VERSION 5.7 ;
  NOWIREEXTENSIONATPIN ON ;
  DIVIDERCHAR "/" ;
  BUSBITCHARS "[]" ;
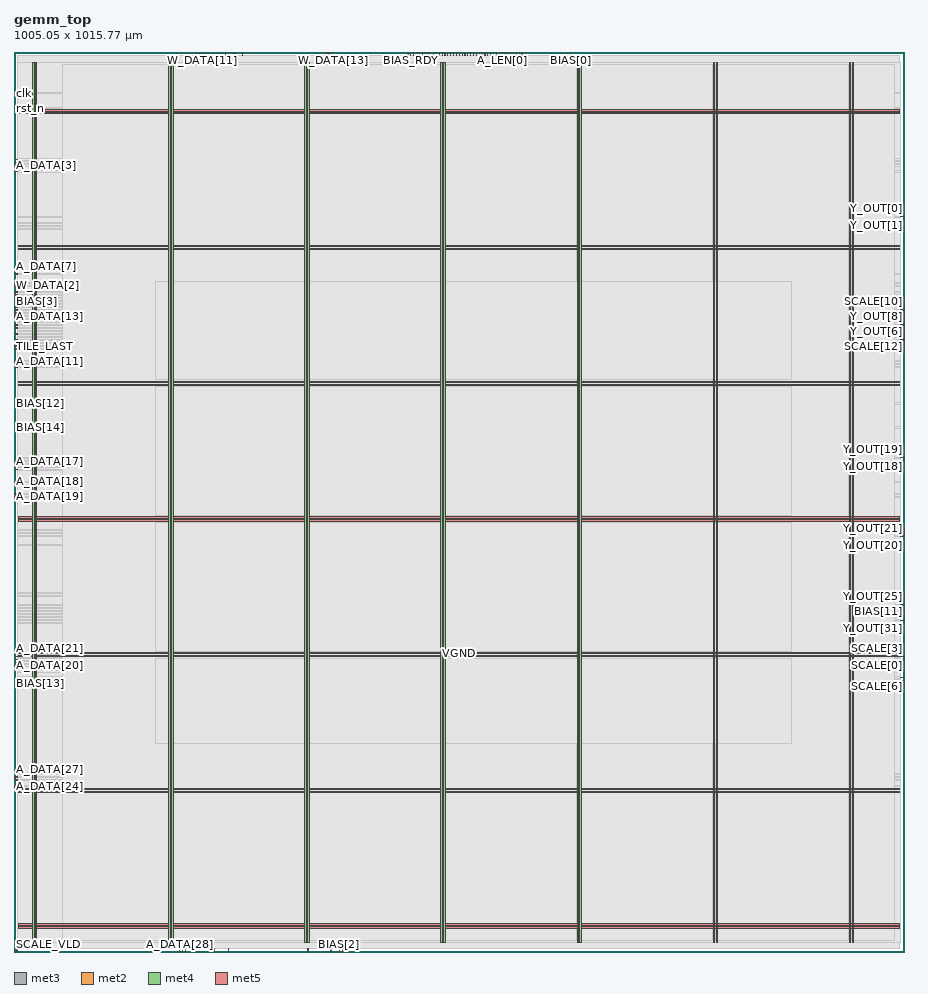
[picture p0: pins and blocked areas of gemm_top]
MACRO gemm_top
  CLASS BLOCK ;
  FOREIGN gemm_top ;
  ORIGIN 0.000 0.000 ;
  SIZE 1005.050 BY 1015.770 ;
  PIN A_DATA[0]
    DIRECTION INPUT ;
    USE SIGNAL ;
    ANTENNAGATEAREA 0.213000 ;
    PORT
      LAYER met3 ;
        RECT 0.000 894.240 4.000 894.840 ;
    END
  END A_DATA[0]
  PIN A_DATA[10]
    DIRECTION INPUT ;
    USE SIGNAL ;
    ANTENNAGATEAREA 0.213000 ;
    PORT
      LAYER met3 ;
        RECT 0.000 697.040 4.000 697.640 ;
    END
  END A_DATA[10]
  PIN A_DATA[11]
    DIRECTION INPUT ;
    USE SIGNAL ;
    ANTENNAGATEAREA 0.213000 ;
    PORT
      LAYER met3 ;
        RECT 0.000 666.440 4.000 667.040 ;
    END
  END A_DATA[11]
  PIN A_DATA[12]
    DIRECTION INPUT ;
    USE SIGNAL ;
    ANTENNAGATEAREA 0.159000 ;
    PORT
      LAYER met3 ;
        RECT 0.000 707.240 4.000 707.840 ;
    END
  END A_DATA[12]
  PIN A_DATA[13]
    DIRECTION INPUT ;
    USE SIGNAL ;
    ANTENNAGATEAREA 0.159000 ;
    PORT
      LAYER met3 ;
        RECT 0.000 717.440 4.000 718.040 ;
    END
  END A_DATA[13]
  PIN A_DATA[14]
    DIRECTION INPUT ;
    USE SIGNAL ;
    ANTENNAGATEAREA 0.159000 ;
    PORT
      LAYER met3 ;
        RECT 0.000 720.840 4.000 721.440 ;
    END
  END A_DATA[14]
  PIN A_DATA[15]
    DIRECTION INPUT ;
    USE SIGNAL ;
    ANTENNAGATEAREA 0.159000 ;
    PORT
      LAYER met3 ;
        RECT 0.000 703.840 4.000 704.440 ;
    END
  END A_DATA[15]
  PIN A_DATA[16]
    DIRECTION INPUT ;
    USE SIGNAL ;
    ANTENNAGATEAREA 0.213000 ;
    PORT
      LAYER met3 ;
        RECT 0.000 516.840 4.000 517.440 ;
    END
  END A_DATA[16]
  PIN A_DATA[17]
    DIRECTION INPUT ;
    USE SIGNAL ;
    ANTENNAGATEAREA 0.213000 ;
    PORT
      LAYER met3 ;
        RECT 0.000 544.040 4.000 544.640 ;
    END
  END A_DATA[17]
  PIN A_DATA[18]
    DIRECTION INPUT ;
    USE SIGNAL ;
    ANTENNAGATEAREA 0.213000 ;
    PORT
      LAYER met3 ;
        RECT 0.000 530.440 4.000 531.040 ;
    END
  END A_DATA[18]
  PIN A_DATA[19]
    DIRECTION INPUT ;
    USE SIGNAL ;
    ANTENNAGATEAREA 0.213000 ;
    PORT
      LAYER met3 ;
        RECT 0.000 513.440 4.000 514.040 ;
    END
  END A_DATA[19]
  PIN A_DATA[1]
    DIRECTION INPUT ;
    USE SIGNAL ;
    ANTENNAGATEAREA 0.213000 ;
    PORT
      LAYER met3 ;
        RECT 0.000 880.640 4.000 881.240 ;
    END
  END A_DATA[1]
  PIN A_DATA[20]
    DIRECTION INPUT ;
    USE SIGNAL ;
    ANTENNAGATEAREA 0.159000 ;
    PORT
      LAYER met3 ;
        RECT 0.000 323.040 4.000 323.640 ;
    END
  END A_DATA[20]
  PIN A_DATA[21]
    DIRECTION INPUT ;
    USE SIGNAL ;
    ANTENNAGATEAREA 0.159000 ;
    PORT
      LAYER met3 ;
        RECT 0.000 333.240 4.000 333.840 ;
    END
  END A_DATA[21]
  PIN A_DATA[22]
    DIRECTION INPUT ;
    USE SIGNAL ;
    ANTENNAGATEAREA 0.159000 ;
    PORT
      LAYER met3 ;
        RECT 0.000 326.440 4.000 327.040 ;
    END
  END A_DATA[22]
  PIN A_DATA[23]
    DIRECTION INPUT ;
    USE SIGNAL ;
    ANTENNAGATEAREA 0.213000 ;
    PORT
      LAYER met3 ;
        RECT 0.000 329.840 4.000 330.440 ;
    END
  END A_DATA[23]
  PIN A_DATA[24]
    DIRECTION INPUT ;
    USE SIGNAL ;
    ANTENNAGATEAREA 0.159000 ;
    PORT
      LAYER met3 ;
        RECT 0.000 187.040 4.000 187.640 ;
    END
  END A_DATA[24]
  PIN A_DATA[25]
    DIRECTION INPUT ;
    USE SIGNAL ;
    ANTENNAGATEAREA 0.159000 ;
    PORT
      LAYER met3 ;
        RECT 0.000 193.840 4.000 194.440 ;
    END
  END A_DATA[25]
  PIN A_DATA[26]
    DIRECTION INPUT ;
    USE SIGNAL ;
    ANTENNAGATEAREA 0.159000 ;
    PORT
      LAYER met3 ;
        RECT 0.000 200.640 4.000 201.240 ;
    END
  END A_DATA[26]
  PIN A_DATA[27]
    DIRECTION INPUT ;
    USE SIGNAL ;
    ANTENNAGATEAREA 0.159000 ;
    PORT
      LAYER met3 ;
        RECT 0.000 197.240 4.000 197.840 ;
    END
  END A_DATA[27]
  PIN A_DATA[28]
    DIRECTION INPUT ;
    USE SIGNAL ;
    ANTENNAGATEAREA 0.213000 ;
    PORT
      LAYER met2 ;
        RECT 186.850 0.000 187.130 4.000 ;
    END
  END A_DATA[28]
  PIN A_DATA[29]
    DIRECTION INPUT ;
    USE SIGNAL ;
    ANTENNAGATEAREA 0.159000 ;
    PORT
      LAYER met2 ;
        RECT 190.070 0.000 190.350 4.000 ;
    END
  END A_DATA[29]
  PIN A_DATA[2]
    DIRECTION INPUT ;
    USE SIGNAL ;
    ANTENNAGATEAREA 0.159000 ;
    PORT
      LAYER met3 ;
        RECT 0.000 890.840 4.000 891.440 ;
    END
  END A_DATA[2]
  PIN A_DATA[30]
    DIRECTION INPUT ;
    USE SIGNAL ;
    ANTENNAGATEAREA 0.213000 ;
    PORT
      LAYER met2 ;
        RECT 193.290 0.000 193.570 4.000 ;
    END
  END A_DATA[30]
  PIN A_DATA[31]
    DIRECTION INPUT ;
    USE SIGNAL ;
    ANTENNAGATEAREA 0.159000 ;
    PORT
      LAYER met2 ;
        RECT 202.950 0.000 203.230 4.000 ;
    END
  END A_DATA[31]
  PIN A_DATA[3]
    DIRECTION INPUT ;
    USE SIGNAL ;
    ANTENNAGATEAREA 0.213000 ;
    PORT
      LAYER met3 ;
        RECT 0.000 887.440 4.000 888.040 ;
    END
  END A_DATA[3]
  PIN A_DATA[4]
    DIRECTION INPUT ;
    USE SIGNAL ;
    ANTENNAGATEAREA 0.213000 ;
    PORT
      LAYER met3 ;
        RECT 0.000 741.240 4.000 741.840 ;
    END
  END A_DATA[4]
  PIN A_DATA[5]
    DIRECTION INPUT ;
    USE SIGNAL ;
    ANTENNAGATEAREA 0.213000 ;
    PORT
      LAYER met3 ;
        RECT 0.000 727.640 4.000 728.240 ;
    END
  END A_DATA[5]
  PIN A_DATA[6]
    DIRECTION INPUT ;
    USE SIGNAL ;
    ANTENNAGATEAREA 0.213000 ;
    PORT
      LAYER met3 ;
        RECT 0.000 724.240 4.000 724.840 ;
    END
  END A_DATA[6]
  PIN A_DATA[7]
    DIRECTION INPUT ;
    USE SIGNAL ;
    ANTENNAGATEAREA 0.213000 ;
    PORT
      LAYER met3 ;
        RECT 0.000 765.040 4.000 765.640 ;
    END
  END A_DATA[7]
  PIN A_DATA[8]
    DIRECTION INPUT ;
    USE SIGNAL ;
    ANTENNAGATEAREA 0.213000 ;
    PORT
      LAYER met3 ;
        RECT 0.000 663.040 4.000 663.640 ;
    END
  END A_DATA[8]
  PIN A_DATA[9]
    DIRECTION INPUT ;
    USE SIGNAL ;
    ANTENNAGATEAREA 0.213000 ;
    PORT
      LAYER met3 ;
        RECT 0.000 680.040 4.000 680.640 ;
    END
  END A_DATA[9]
  PIN A_LEN[0]
    DIRECTION INPUT ;
    USE SIGNAL ;
    ANTENNAGATEAREA 0.213000 ;
    PORT
      LAYER met2 ;
        RECT 550.710 1011.770 550.990 1015.770 ;
    END
  END A_LEN[0]
  PIN A_LEN[1]
    DIRECTION INPUT ;
    USE SIGNAL ;
    ANTENNAGATEAREA 0.159000 ;
    PORT
      LAYER met2 ;
        RECT 547.490 1011.770 547.770 1015.770 ;
    END
  END A_LEN[1]
  PIN A_LEN[2]
    DIRECTION INPUT ;
    USE SIGNAL ;
    ANTENNAGATEAREA 0.213000 ;
    PORT
      LAYER met2 ;
        RECT 531.390 1011.770 531.670 1015.770 ;
    END
  END A_LEN[2]
  PIN A_LEN[3]
    DIRECTION INPUT ;
    USE SIGNAL ;
    ANTENNAGATEAREA 0.213000 ;
    PORT
      LAYER met2 ;
        RECT 515.290 1011.770 515.570 1015.770 ;
    END
  END A_LEN[3]
  PIN BIAS[0]
    DIRECTION INPUT ;
    USE SIGNAL ;
    ANTENNAGATEAREA 0.742500 ;
    PORT
      LAYER met2 ;
        RECT 627.990 1011.770 628.270 1015.770 ;
    END
  END BIAS[0]
  PIN BIAS[10]
    DIRECTION INPUT ;
    USE SIGNAL ;
    ANTENNAGATEAREA 0.742500 ;
    PORT
      LAYER met2 ;
        RECT 225.490 0.000 225.770 4.000 ;
    END
  END BIAS[10]
  PIN BIAS[11]
    DIRECTION INPUT ;
    USE SIGNAL ;
    ANTENNAGATEAREA 0.495000 ;
    PORT
      LAYER met3 ;
        RECT 1001.050 384.240 1005.050 384.840 ;
    END
  END BIAS[11]
  PIN BIAS[12]
    DIRECTION INPUT ;
    USE SIGNAL ;
    ANTENNAGATEAREA 0.990000 ;
    PORT
      LAYER met3 ;
        RECT 0.000 618.840 4.000 619.440 ;
    END
  END BIAS[12]
  PIN BIAS[13]
    DIRECTION INPUT ;
    USE SIGNAL ;
    ANTENNAGATEAREA 0.852000 ;
    PORT
      LAYER met3 ;
        RECT 0.000 302.640 4.000 303.240 ;
    END
  END BIAS[13]
  PIN BIAS[14]
    DIRECTION INPUT ;
    USE SIGNAL ;
    ANTENNAGATEAREA 0.247500 ;
    PORT
      LAYER met3 ;
        RECT 0.000 591.640 4.000 592.240 ;
    END
  END BIAS[14]
  PIN BIAS[15]
    DIRECTION INPUT ;
    USE SIGNAL ;
    ANTENNAGATEAREA 0.426000 ;
    PORT
      LAYER met3 ;
        RECT 0.000 690.240 4.000 690.840 ;
    END
  END BIAS[15]
  PIN BIAS[1]
    DIRECTION INPUT ;
    USE SIGNAL ;
    ANTENNAGATEAREA 0.742500 ;
    PORT
      LAYER met2 ;
        RECT 444.450 1011.770 444.730 1015.770 ;
    END
  END BIAS[1]
  PIN BIAS[2]
    DIRECTION INPUT ;
    USE SIGNAL ;
    ANTENNAGATEAREA 0.742500 ;
    PORT
      LAYER met2 ;
        RECT 367.170 0.000 367.450 4.000 ;
    END
  END BIAS[2]
  PIN BIAS[3]
    DIRECTION INPUT ;
    USE SIGNAL ;
    ANTENNAGATEAREA 0.742500 ;
    PORT
      LAYER met3 ;
        RECT 0.000 734.440 4.000 735.040 ;
    END
  END BIAS[3]
  PIN BIAS[4]
    DIRECTION INPUT ;
    USE SIGNAL ;
    ANTENNAGATEAREA 0.852000 ;
    PORT
      LAYER met2 ;
        RECT 241.590 0.000 241.870 4.000 ;
    END
  END BIAS[4]
  PIN BIAS[5]
    DIRECTION INPUT ;
    USE SIGNAL ;
    ANTENNAGATEAREA 0.990000 ;
    PORT
      LAYER met2 ;
        RECT 370.390 0.000 370.670 4.000 ;
    END
  END BIAS[5]
  PIN BIAS[6]
    DIRECTION INPUT ;
    USE SIGNAL ;
    ANTENNAGATEAREA 0.742500 ;
    PORT
      LAYER met2 ;
        RECT 331.750 0.000 332.030 4.000 ;
    END
  END BIAS[6]
  PIN BIAS[7]
    DIRECTION INPUT ;
    USE SIGNAL ;
    ANTENNAGATEAREA 0.495000 ;
    PORT
      LAYER met2 ;
        RECT 357.510 0.000 357.790 4.000 ;
    END
  END BIAS[7]
  PIN BIAS[8]
    DIRECTION INPUT ;
    USE SIGNAL ;
    ANTENNAGATEAREA 0.990000 ;
    PORT
      LAYER met2 ;
        RECT 373.610 0.000 373.890 4.000 ;
    END
  END BIAS[8]
  PIN BIAS[9]
    DIRECTION INPUT ;
    USE SIGNAL ;
    ANTENNAGATEAREA 0.495000 ;
    PORT
      LAYER met3 ;
        RECT 0.000 659.640 4.000 660.240 ;
    END
  END BIAS[9]
  PIN BIAS_NEW
    DIRECTION INPUT ;
    USE SIGNAL ;
    ANTENNAGATEAREA 0.196500 ;
    PORT
      LAYER met2 ;
        RECT 537.830 1011.770 538.110 1015.770 ;
    END
  END BIAS_NEW
  PIN BIAS_RDY
    DIRECTION OUTPUT ;
    USE SIGNAL ;
    ANTENNADIFFAREA 0.445500 ;
    PORT
      LAYER met2 ;
        RECT 447.670 1011.770 447.950 1015.770 ;
    END
  END BIAS_RDY
  PIN BIAS_VLD
    DIRECTION INPUT ;
    USE SIGNAL ;
    ANTENNAGATEAREA 0.196500 ;
    PORT
      LAYER met2 ;
        RECT 454.110 1011.770 454.390 1015.770 ;
    END
  END BIAS_VLD
  PIN DATA_RDY
    DIRECTION OUTPUT ;
    USE SIGNAL ;
    ANTENNADIFFAREA 0.445500 ;
    PORT
      LAYER met2 ;
        RECT 483.090 1011.770 483.370 1015.770 ;
    END
  END DATA_RDY
  PIN DATA_VLD
    DIRECTION INPUT ;
    USE SIGNAL ;
    ANTENNAGATEAREA 0.196500 ;
    PORT
      LAYER met2 ;
        RECT 470.210 1011.770 470.490 1015.770 ;
    END
  END DATA_VLD
  PIN K_LEN[0]
    DIRECTION INPUT ;
    USE SIGNAL ;
    ANTENNAGATEAREA 0.196500 ;
    PORT
      LAYER met2 ;
        RECT 466.990 1011.770 467.270 1015.770 ;
    END
  END K_LEN[0]
  PIN K_LEN[1]
    DIRECTION INPUT ;
    USE SIGNAL ;
    ANTENNAGATEAREA 0.196500 ;
    PORT
      LAYER met2 ;
        RECT 463.770 1011.770 464.050 1015.770 ;
    END
  END K_LEN[1]
  PIN K_LEN[2]
    DIRECTION INPUT ;
    USE SIGNAL ;
    ANTENNAGATEAREA 0.196500 ;
    PORT
      LAYER met2 ;
        RECT 499.190 1011.770 499.470 1015.770 ;
    END
  END K_LEN[2]
  PIN K_LEN[3]
    DIRECTION INPUT ;
    USE SIGNAL ;
    ANTENNAGATEAREA 0.126000 ;
    PORT
      LAYER met2 ;
        RECT 521.730 1011.770 522.010 1015.770 ;
    END
  END K_LEN[3]
  PIN METADATA_RDY
    DIRECTION OUTPUT ;
    USE SIGNAL ;
    ANTENNADIFFAREA 0.445500 ;
    PORT
      LAYER met2 ;
        RECT 450.890 1011.770 451.170 1015.770 ;
    END
  END METADATA_RDY
  PIN METADATA_VLD
    DIRECTION INPUT ;
    USE SIGNAL ;
    ANTENNAGATEAREA 0.196500 ;
    PORT
      LAYER met2 ;
        RECT 457.330 1011.770 457.610 1015.770 ;
    END
  END METADATA_VLD
  PIN RELU_EN
    DIRECTION INPUT ;
    USE SIGNAL ;
    ANTENNAGATEAREA 0.196500 ;
    PORT
      LAYER met2 ;
        RECT 528.170 1011.770 528.450 1015.770 ;
    END
  END RELU_EN
  PIN SCALE[0]
    DIRECTION INPUT ;
    USE SIGNAL ;
    ANTENNAGATEAREA 0.159000 ;
    PORT
      LAYER met3 ;
        RECT 1001.050 323.040 1005.050 323.640 ;
    END
  END SCALE[0]
  PIN SCALE[10]
    DIRECTION INPUT ;
    USE SIGNAL ;
    ANTENNAGATEAREA 0.213000 ;
    PORT
      LAYER met3 ;
        RECT 1001.050 734.440 1005.050 735.040 ;
    END
  END SCALE[10]
  PIN SCALE[11]
    DIRECTION INPUT ;
    USE SIGNAL ;
    ANTENNAGATEAREA 0.196500 ;
    PORT
      LAYER met3 ;
        RECT 1001.050 727.640 1005.050 728.240 ;
    END
  END SCALE[11]
  PIN SCALE[12]
    DIRECTION INPUT ;
    USE SIGNAL ;
    ANTENNAGATEAREA 0.126000 ;
    PORT
      LAYER met3 ;
        RECT 1001.050 683.440 1005.050 684.040 ;
    END
  END SCALE[12]
  PIN SCALE[13]
    DIRECTION INPUT ;
    USE SIGNAL ;
    ANTENNAGATEAREA 0.159000 ;
    PORT
      LAYER met3 ;
        RECT 1001.050 720.840 1005.050 721.440 ;
    END
  END SCALE[13]
  PIN SCALE[14]
    DIRECTION INPUT ;
    USE SIGNAL ;
    ANTENNAGATEAREA 0.426000 ;
    PORT
      LAYER met3 ;
        RECT 1001.050 731.040 1005.050 731.640 ;
    END
  END SCALE[14]
  PIN SCALE[15]
    DIRECTION INPUT ;
    USE SIGNAL ;
    PORT
      LAYER met2 ;
        RECT 0.090 0.000 0.370 4.000 ;
    END
  END SCALE[15]
  PIN SCALE[1]
    DIRECTION INPUT ;
    USE SIGNAL ;
    ANTENNAGATEAREA 0.196500 ;
    PORT
      LAYER met3 ;
        RECT 1001.050 326.440 1005.050 327.040 ;
    END
  END SCALE[1]
  PIN SCALE[2]
    DIRECTION INPUT ;
    USE SIGNAL ;
    ANTENNAGATEAREA 0.196500 ;
    PORT
      LAYER met3 ;
        RECT 1001.050 329.840 1005.050 330.440 ;
    END
  END SCALE[2]
  PIN SCALE[3]
    DIRECTION INPUT ;
    USE SIGNAL ;
    ANTENNAGATEAREA 0.196500 ;
    PORT
      LAYER met3 ;
        RECT 1001.050 333.240 1005.050 333.840 ;
    END
  END SCALE[3]
  PIN SCALE[4]
    DIRECTION INPUT ;
    USE SIGNAL ;
    ANTENNAGATEAREA 0.196500 ;
    PORT
      LAYER met3 ;
        RECT 1001.050 336.640 1005.050 337.240 ;
    END
  END SCALE[4]
  PIN SCALE[5]
    DIRECTION INPUT ;
    USE SIGNAL ;
    ANTENNAGATEAREA 0.213000 ;
    PORT
      LAYER met3 ;
        RECT 1001.050 316.240 1005.050 316.840 ;
    END
  END SCALE[5]
  PIN SCALE[6]
    DIRECTION INPUT ;
    USE SIGNAL ;
    ANTENNAGATEAREA 0.247500 ;
    PORT
      LAYER met3 ;
        RECT 1001.050 299.240 1005.050 299.840 ;
    END
  END SCALE[6]
  PIN SCALE[7]
    DIRECTION INPUT ;
    USE SIGNAL ;
    ANTENNAGATEAREA 0.196500 ;
    PORT
      LAYER met3 ;
        RECT 1001.050 302.640 1005.050 303.240 ;
    END
  END SCALE[7]
  PIN SCALE[8]
    DIRECTION INPUT ;
    USE SIGNAL ;
    ANTENNAGATEAREA 0.247500 ;
    PORT
      LAYER met3 ;
        RECT 1001.050 306.040 1005.050 306.640 ;
    END
  END SCALE[8]
  PIN SCALE[9]
    DIRECTION INPUT ;
    USE SIGNAL ;
    ANTENNAGATEAREA 0.159000 ;
    PORT
      LAYER met3 ;
        RECT 1001.050 309.440 1005.050 310.040 ;
    END
  END SCALE[9]
  PIN SCALE_RDY
    DIRECTION OUTPUT ;
    USE SIGNAL ;
    ANTENNADIFFAREA 0.445500 ;
    PORT
      LAYER met2 ;
        RECT 508.850 1011.770 509.130 1015.770 ;
    END
  END SCALE_RDY
  PIN SCALE_VLD
    DIRECTION INPUT ;
    USE SIGNAL ;
    PORT
      LAYER met2 ;
        RECT 3.310 0.000 3.590 4.000 ;
    END
  END SCALE_VLD
  PIN TILE_DONE
    DIRECTION OUTPUT ;
    USE SIGNAL ;
    ANTENNADIFFAREA 0.445500 ;
    PORT
      LAYER met2 ;
        RECT 492.750 1011.770 493.030 1015.770 ;
    END
  END TILE_DONE
  PIN TILE_LAST
    DIRECTION INPUT ;
    USE SIGNAL ;
    ANTENNAGATEAREA 0.247500 ;
    PORT
      LAYER met3 ;
        RECT 0.000 683.440 4.000 684.040 ;
    END
  END TILE_LAST
  PIN TILE_START
    DIRECTION INPUT ;
    USE SIGNAL ;
    ANTENNAGATEAREA 0.196500 ;
    PORT
      LAYER met2 ;
        RECT 473.430 1011.770 473.710 1015.770 ;
    END
  END TILE_START
  PIN VGND
    DIRECTION INOUT ;
    USE GROUND ;
    PORT
      LAYER met4 ;
        RECT 24.340 10.640 25.940 1003.920 ;
    END
    PORT
      LAYER met4 ;
        RECT 177.940 10.640 179.540 1003.920 ;
    END
    PORT
      LAYER met4 ;
        RECT 331.540 10.640 333.140 1003.920 ;
    END
    PORT
      LAYER met4 ;
        RECT 485.140 10.640 486.740 1003.920 ;
    END
    PORT
      LAYER met4 ;
        RECT 638.740 10.640 640.340 1003.920 ;
    END
    PORT
      LAYER met4 ;
        RECT 792.340 10.640 793.940 1003.920 ;
    END
    PORT
      LAYER met4 ;
        RECT 945.940 10.640 947.540 1003.920 ;
    END
    PORT
      LAYER met5 ;
        RECT 5.280 30.030 999.360 31.630 ;
    END
    PORT
      LAYER met5 ;
        RECT 5.280 183.210 999.360 184.810 ;
    END
    PORT
      LAYER met5 ;
        RECT 5.280 336.390 999.360 337.990 ;
    END
    PORT
      LAYER met5 ;
        RECT 5.280 489.570 999.360 491.170 ;
    END
    PORT
      LAYER met5 ;
        RECT 5.280 642.750 999.360 644.350 ;
    END
    PORT
      LAYER met5 ;
        RECT 5.280 795.930 999.360 797.530 ;
    END
    PORT
      LAYER met5 ;
        RECT 5.280 949.110 999.360 950.710 ;
    END
  END VGND
  PIN VPWR
    DIRECTION INOUT ;
    USE POWER ;
    PORT
      LAYER met4 ;
        RECT 21.040 10.640 22.640 1003.920 ;
    END
    PORT
      LAYER met4 ;
        RECT 174.640 10.640 176.240 1003.920 ;
    END
    PORT
      LAYER met4 ;
        RECT 328.240 10.640 329.840 1003.920 ;
    END
    PORT
      LAYER met4 ;
        RECT 481.840 10.640 483.440 1003.920 ;
    END
    PORT
      LAYER met4 ;
        RECT 635.440 10.640 637.040 1003.920 ;
    END
    PORT
      LAYER met4 ;
        RECT 789.040 10.640 790.640 1003.920 ;
    END
    PORT
      LAYER met4 ;
        RECT 942.640 10.640 944.240 1003.920 ;
    END
    PORT
      LAYER met5 ;
        RECT 5.280 26.730 999.360 28.330 ;
    END
    PORT
      LAYER met5 ;
        RECT 5.280 179.910 999.360 181.510 ;
    END
    PORT
      LAYER met5 ;
        RECT 5.280 333.090 999.360 334.690 ;
    END
    PORT
      LAYER met5 ;
        RECT 5.280 486.270 999.360 487.870 ;
    END
    PORT
      LAYER met5 ;
        RECT 5.280 639.450 999.360 641.050 ;
    END
    PORT
      LAYER met5 ;
        RECT 5.280 792.630 999.360 794.230 ;
    END
    PORT
      LAYER met5 ;
        RECT 5.280 945.810 999.360 947.410 ;
    END
  END VPWR
  PIN W_DATA[0]
    DIRECTION INPUT ;
    USE SIGNAL ;
    ANTENNAGATEAREA 0.213000 ;
    PORT
      LAYER met3 ;
        RECT 0.000 737.840 4.000 738.440 ;
    END
  END W_DATA[0]
  PIN W_DATA[10]
    DIRECTION INPUT ;
    USE SIGNAL ;
    ANTENNAGATEAREA 0.213000 ;
    PORT
      LAYER met2 ;
        RECT 183.630 1011.770 183.910 1015.770 ;
    END
  END W_DATA[10]
  PIN W_DATA[11]
    DIRECTION INPUT ;
    USE SIGNAL ;
    ANTENNAGATEAREA 0.213000 ;
    PORT
      LAYER met2 ;
        RECT 212.610 1011.770 212.890 1015.770 ;
    END
  END W_DATA[11]
  PIN W_DATA[12]
    DIRECTION INPUT ;
    USE SIGNAL ;
    ANTENNAGATEAREA 0.213000 ;
    PORT
      LAYER met2 ;
        RECT 351.070 1011.770 351.350 1015.770 ;
    END
  END W_DATA[12]
  PIN W_DATA[13]
    DIRECTION INPUT ;
    USE SIGNAL ;
    ANTENNAGATEAREA 0.213000 ;
    PORT
      LAYER met2 ;
        RECT 360.730 1011.770 361.010 1015.770 ;
    END
  END W_DATA[13]
  PIN W_DATA[14]
    DIRECTION INPUT ;
    USE SIGNAL ;
    ANTENNAGATEAREA 0.213000 ;
    PORT
      LAYER met2 ;
        RECT 354.290 1011.770 354.570 1015.770 ;
    END
  END W_DATA[14]
  PIN W_DATA[15]
    DIRECTION INPUT ;
    USE SIGNAL ;
    ANTENNAGATEAREA 0.213000 ;
    PORT
      LAYER met2 ;
        RECT 357.510 1011.770 357.790 1015.770 ;
    END
  END W_DATA[15]
  PIN W_DATA[16]
    DIRECTION INPUT ;
    USE SIGNAL ;
    ANTENNAGATEAREA 0.213000 ;
    PORT
      LAYER met2 ;
        RECT 460.550 1011.770 460.830 1015.770 ;
    END
  END W_DATA[16]
  PIN W_DATA[17]
    DIRECTION INPUT ;
    USE SIGNAL ;
    ANTENNAGATEAREA 0.213000 ;
    PORT
      LAYER met2 ;
        RECT 502.410 1011.770 502.690 1015.770 ;
    END
  END W_DATA[17]
  PIN W_DATA[18]
    DIRECTION INPUT ;
    USE SIGNAL ;
    ANTENNAGATEAREA 0.213000 ;
    PORT
      LAYER met2 ;
        RECT 486.310 1011.770 486.590 1015.770 ;
    END
  END W_DATA[18]
  PIN W_DATA[19]
    DIRECTION INPUT ;
    USE SIGNAL ;
    ANTENNAGATEAREA 0.213000 ;
    PORT
      LAYER met2 ;
        RECT 495.970 1011.770 496.250 1015.770 ;
    END
  END W_DATA[19]
  PIN W_DATA[1]
    DIRECTION INPUT ;
    USE SIGNAL ;
    ANTENNAGATEAREA 0.213000 ;
    PORT
      LAYER met3 ;
        RECT 0.000 754.840 4.000 755.440 ;
    END
  END W_DATA[1]
  PIN W_DATA[20]
    DIRECTION INPUT ;
    USE SIGNAL ;
    ANTENNAGATEAREA 0.159000 ;
    PORT
      LAYER met2 ;
        RECT 489.530 1011.770 489.810 1015.770 ;
    END
  END W_DATA[20]
  PIN W_DATA[21]
    DIRECTION INPUT ;
    USE SIGNAL ;
    ANTENNAGATEAREA 0.159000 ;
    PORT
      LAYER met2 ;
        RECT 476.650 1011.770 476.930 1015.770 ;
    END
  END W_DATA[21]
  PIN W_DATA[22]
    DIRECTION INPUT ;
    USE SIGNAL ;
    ANTENNAGATEAREA 0.213000 ;
    PORT
      LAYER met2 ;
        RECT 524.950 1011.770 525.230 1015.770 ;
    END
  END W_DATA[22]
  PIN W_DATA[23]
    DIRECTION INPUT ;
    USE SIGNAL ;
    ANTENNAGATEAREA 0.159000 ;
    PORT
      LAYER met2 ;
        RECT 479.870 1011.770 480.150 1015.770 ;
    END
  END W_DATA[23]
  PIN W_DATA[24]
    DIRECTION INPUT ;
    USE SIGNAL ;
    ANTENNAGATEAREA 0.159000 ;
    PORT
      LAYER met2 ;
        RECT 563.590 1011.770 563.870 1015.770 ;
    END
  END W_DATA[24]
  PIN W_DATA[25]
    DIRECTION INPUT ;
    USE SIGNAL ;
    ANTENNAGATEAREA 0.213000 ;
    PORT
      LAYER met2 ;
        RECT 553.930 1011.770 554.210 1015.770 ;
    END
  END W_DATA[25]
  PIN W_DATA[26]
    DIRECTION INPUT ;
    USE SIGNAL ;
    ANTENNAGATEAREA 0.159000 ;
    PORT
      LAYER met2 ;
        RECT 541.050 1011.770 541.330 1015.770 ;
    END
  END W_DATA[26]
  PIN W_DATA[27]
    DIRECTION INPUT ;
    USE SIGNAL ;
    ANTENNAGATEAREA 0.213000 ;
    PORT
      LAYER met2 ;
        RECT 560.370 1011.770 560.650 1015.770 ;
    END
  END W_DATA[27]
  PIN W_DATA[28]
    DIRECTION INPUT ;
    USE SIGNAL ;
    ANTENNAGATEAREA 0.159000 ;
    PORT
      LAYER met2 ;
        RECT 557.150 1011.770 557.430 1015.770 ;
    END
  END W_DATA[28]
  PIN W_DATA[29]
    DIRECTION INPUT ;
    USE SIGNAL ;
    ANTENNAGATEAREA 0.159000 ;
    PORT
      LAYER met2 ;
        RECT 573.250 1011.770 573.530 1015.770 ;
    END
  END W_DATA[29]
  PIN W_DATA[2]
    DIRECTION INPUT ;
    USE SIGNAL ;
    ANTENNAGATEAREA 0.213000 ;
    PORT
      LAYER met3 ;
        RECT 0.000 751.440 4.000 752.040 ;
    END
  END W_DATA[2]
  PIN W_DATA[30]
    DIRECTION INPUT ;
    USE SIGNAL ;
    ANTENNAGATEAREA 0.159000 ;
    PORT
      LAYER met2 ;
        RECT 570.030 1011.770 570.310 1015.770 ;
    END
  END W_DATA[30]
  PIN W_DATA[31]
    DIRECTION INPUT ;
    USE SIGNAL ;
    ANTENNAGATEAREA 0.159000 ;
    PORT
      LAYER met2 ;
        RECT 566.810 1011.770 567.090 1015.770 ;
    END
  END W_DATA[31]
  PIN W_DATA[3]
    DIRECTION INPUT ;
    USE SIGNAL ;
    ANTENNAGATEAREA 0.213000 ;
    PORT
      LAYER met3 ;
        RECT 0.000 744.640 4.000 745.240 ;
    END
  END W_DATA[3]
  PIN W_DATA[4]
    DIRECTION INPUT ;
    USE SIGNAL ;
    ANTENNAGATEAREA 0.213000 ;
    PORT
      LAYER met2 ;
        RECT 257.690 1011.770 257.970 1015.770 ;
    END
  END W_DATA[4]
  PIN W_DATA[5]
    DIRECTION INPUT ;
    USE SIGNAL ;
    ANTENNAGATEAREA 0.213000 ;
    PORT
      LAYER met2 ;
        RECT 238.370 1011.770 238.650 1015.770 ;
    END
  END W_DATA[5]
  PIN W_DATA[6]
    DIRECTION INPUT ;
    USE SIGNAL ;
    ANTENNAGATEAREA 0.213000 ;
    PORT
      LAYER met2 ;
        RECT 235.150 1011.770 235.430 1015.770 ;
    END
  END W_DATA[6]
  PIN W_DATA[7]
    DIRECTION INPUT ;
    USE SIGNAL ;
    ANTENNAGATEAREA 0.159000 ;
    PORT
      LAYER met2 ;
        RECT 248.030 1011.770 248.310 1015.770 ;
    END
  END W_DATA[7]
  PIN W_DATA[8]
    DIRECTION INPUT ;
    USE SIGNAL ;
    ANTENNAGATEAREA 0.213000 ;
    PORT
      LAYER met2 ;
        RECT 209.390 1011.770 209.670 1015.770 ;
    END
  END W_DATA[8]
  PIN W_DATA[9]
    DIRECTION INPUT ;
    USE SIGNAL ;
    ANTENNAGATEAREA 0.213000 ;
    PORT
      LAYER met2 ;
        RECT 206.170 1011.770 206.450 1015.770 ;
    END
  END W_DATA[9]
  PIN W_LEN[0]
    DIRECTION INPUT ;
    USE SIGNAL ;
    ANTENNAGATEAREA 0.213000 ;
    PORT
      LAYER met2 ;
        RECT 512.070 1011.770 512.350 1015.770 ;
    END
  END W_LEN[0]
  PIN W_LEN[1]
    DIRECTION INPUT ;
    USE SIGNAL ;
    ANTENNAGATEAREA 0.159000 ;
    PORT
      LAYER met2 ;
        RECT 534.610 1011.770 534.890 1015.770 ;
    END
  END W_LEN[1]
  PIN W_LEN[2]
    DIRECTION INPUT ;
    USE SIGNAL ;
    ANTENNAGATEAREA 0.213000 ;
    PORT
      LAYER met2 ;
        RECT 518.510 1011.770 518.790 1015.770 ;
    END
  END W_LEN[2]
  PIN W_LEN[3]
    DIRECTION INPUT ;
    USE SIGNAL ;
    ANTENNAGATEAREA 0.213000 ;
    PORT
      LAYER met2 ;
        RECT 544.270 1011.770 544.550 1015.770 ;
    END
  END W_LEN[3]
  PIN Y_OUT[0]
    DIRECTION OUTPUT ;
    USE SIGNAL ;
    ANTENNADIFFAREA 0.445500 ;
    PORT
      LAYER met3 ;
        RECT 1001.050 829.640 1005.050 830.240 ;
    END
  END Y_OUT[0]
  PIN Y_OUT[10]
    DIRECTION OUTPUT ;
    USE SIGNAL ;
    ANTENNADIFFAREA 0.445500 ;
    PORT
      LAYER met3 ;
        RECT 1001.050 707.240 1005.050 707.840 ;
    END
  END Y_OUT[10]
  PIN Y_OUT[11]
    DIRECTION OUTPUT ;
    USE SIGNAL ;
    ANTENNADIFFAREA 0.445500 ;
    PORT
      LAYER met3 ;
        RECT 1001.050 686.840 1005.050 687.440 ;
    END
  END Y_OUT[11]
  PIN Y_OUT[12]
    DIRECTION OUTPUT ;
    USE SIGNAL ;
    ANTENNADIFFAREA 0.445500 ;
    PORT
      LAYER met3 ;
        RECT 1001.050 703.840 1005.050 704.440 ;
    END
  END Y_OUT[12]
  PIN Y_OUT[13]
    DIRECTION OUTPUT ;
    USE SIGNAL ;
    ANTENNADIFFAREA 0.445500 ;
    PORT
      LAYER met3 ;
        RECT 1001.050 710.640 1005.050 711.240 ;
    END
  END Y_OUT[13]
  PIN Y_OUT[14]
    DIRECTION OUTPUT ;
    USE SIGNAL ;
    ANTENNADIFFAREA 0.445500 ;
    PORT
      LAYER met3 ;
        RECT 1001.050 690.240 1005.050 690.840 ;
    END
  END Y_OUT[14]
  PIN Y_OUT[15]
    DIRECTION OUTPUT ;
    USE SIGNAL ;
    ANTENNADIFFAREA 0.445500 ;
    PORT
      LAYER met3 ;
        RECT 1001.050 680.040 1005.050 680.640 ;
    END
  END Y_OUT[15]
  PIN Y_OUT[16]
    DIRECTION OUTPUT ;
    USE SIGNAL ;
    ANTENNADIFFAREA 0.445500 ;
    PORT
      LAYER met3 ;
        RECT 1001.050 550.840 1005.050 551.440 ;
    END
  END Y_OUT[16]
  PIN Y_OUT[17]
    DIRECTION OUTPUT ;
    USE SIGNAL ;
    ANTENNADIFFAREA 0.445500 ;
    PORT
      LAYER met3 ;
        RECT 1001.050 554.240 1005.050 554.840 ;
    END
  END Y_OUT[17]
  PIN Y_OUT[18]
    DIRECTION OUTPUT ;
    USE SIGNAL ;
    ANTENNADIFFAREA 0.445500 ;
    PORT
      LAYER met3 ;
        RECT 1001.050 547.440 1005.050 548.040 ;
    END
  END Y_OUT[18]
  PIN Y_OUT[19]
    DIRECTION OUTPUT ;
    USE SIGNAL ;
    ANTENNADIFFAREA 0.445500 ;
    PORT
      LAYER met3 ;
        RECT 1001.050 557.640 1005.050 558.240 ;
    END
  END Y_OUT[19]
  PIN Y_OUT[1]
    DIRECTION OUTPUT ;
    USE SIGNAL ;
    ANTENNADIFFAREA 0.445500 ;
    PORT
      LAYER met3 ;
        RECT 1001.050 819.440 1005.050 820.040 ;
    END
  END Y_OUT[1]
  PIN Y_OUT[20]
    DIRECTION OUTPUT ;
    USE SIGNAL ;
    ANTENNADIFFAREA 0.445500 ;
    PORT
      LAYER met3 ;
        RECT 1001.050 459.040 1005.050 459.640 ;
    END
  END Y_OUT[20]
  PIN Y_OUT[21]
    DIRECTION OUTPUT ;
    USE SIGNAL ;
    ANTENNADIFFAREA 0.445500 ;
    PORT
      LAYER met3 ;
        RECT 1001.050 469.240 1005.050 469.840 ;
    END
  END Y_OUT[21]
  PIN Y_OUT[22]
    DIRECTION OUTPUT ;
    USE SIGNAL ;
    ANTENNADIFFAREA 0.445500 ;
    PORT
      LAYER met3 ;
        RECT 1001.050 472.640 1005.050 473.240 ;
    END
  END Y_OUT[22]
  PIN Y_OUT[23]
    DIRECTION OUTPUT ;
    USE SIGNAL ;
    ANTENNADIFFAREA 0.445500 ;
    PORT
      LAYER met3 ;
        RECT 1001.050 476.040 1005.050 476.640 ;
    END
  END Y_OUT[23]
  PIN Y_OUT[24]
    DIRECTION OUTPUT ;
    USE SIGNAL ;
    ANTENNADIFFAREA 0.445500 ;
    PORT
      LAYER met3 ;
        RECT 1001.050 391.040 1005.050 391.640 ;
    END
  END Y_OUT[24]
  PIN Y_OUT[25]
    DIRECTION OUTPUT ;
    USE SIGNAL ;
    ANTENNADIFFAREA 0.445500 ;
    PORT
      LAYER met3 ;
        RECT 1001.050 401.240 1005.050 401.840 ;
    END
  END Y_OUT[25]
  PIN Y_OUT[26]
    DIRECTION OUTPUT ;
    USE SIGNAL ;
    ANTENNADIFFAREA 0.445500 ;
    PORT
      LAYER met3 ;
        RECT 1001.050 387.640 1005.050 388.240 ;
    END
  END Y_OUT[26]
  PIN Y_OUT[27]
    DIRECTION OUTPUT ;
    USE SIGNAL ;
    ANTENNADIFFAREA 0.445500 ;
    PORT
      LAYER met3 ;
        RECT 1001.050 404.640 1005.050 405.240 ;
    END
  END Y_OUT[27]
  PIN Y_OUT[28]
    DIRECTION OUTPUT ;
    USE SIGNAL ;
    ANTENNADIFFAREA 0.445500 ;
    PORT
      LAYER met3 ;
        RECT 1001.050 377.440 1005.050 378.040 ;
    END
  END Y_OUT[28]
  PIN Y_OUT[29]
    DIRECTION OUTPUT ;
    USE SIGNAL ;
    ANTENNADIFFAREA 0.445500 ;
    PORT
      LAYER met3 ;
        RECT 1001.050 380.840 1005.050 381.440 ;
    END
  END Y_OUT[29]
  PIN Y_OUT[2]
    DIRECTION OUTPUT ;
    USE SIGNAL ;
    ANTENNADIFFAREA 0.445500 ;
    PORT
      LAYER met3 ;
        RECT 1001.050 816.040 1005.050 816.640 ;
    END
  END Y_OUT[2]
  PIN Y_OUT[30]
    DIRECTION OUTPUT ;
    USE SIGNAL ;
    ANTENNADIFFAREA 0.445500 ;
    PORT
      LAYER met3 ;
        RECT 1001.050 370.640 1005.050 371.240 ;
    END
  END Y_OUT[30]
  PIN Y_OUT[31]
    DIRECTION OUTPUT ;
    USE SIGNAL ;
    ANTENNADIFFAREA 0.445500 ;
    PORT
      LAYER met3 ;
        RECT 1001.050 374.040 1005.050 374.640 ;
    END
  END Y_OUT[31]
  PIN Y_OUT[3]
    DIRECTION OUTPUT ;
    USE SIGNAL ;
    ANTENNADIFFAREA 0.445500 ;
    PORT
      LAYER met3 ;
        RECT 1001.050 822.840 1005.050 823.440 ;
    END
  END Y_OUT[3]
  PIN Y_OUT[4]
    DIRECTION OUTPUT ;
    USE SIGNAL ;
    ANTENNADIFFAREA 0.445500 ;
    PORT
      LAYER met3 ;
        RECT 1001.050 714.040 1005.050 714.640 ;
    END
  END Y_OUT[4]
  PIN Y_OUT[5]
    DIRECTION OUTPUT ;
    USE SIGNAL ;
    ANTENNADIFFAREA 0.445500 ;
    PORT
      LAYER met3 ;
        RECT 1001.050 697.040 1005.050 697.640 ;
    END
  END Y_OUT[5]
  PIN Y_OUT[6]
    DIRECTION OUTPUT ;
    USE SIGNAL ;
    ANTENNADIFFAREA 0.445500 ;
    PORT
      LAYER met3 ;
        RECT 1001.050 700.440 1005.050 701.040 ;
    END
  END Y_OUT[6]
  PIN Y_OUT[7]
    DIRECTION OUTPUT ;
    USE SIGNAL ;
    ANTENNADIFFAREA 0.445500 ;
    PORT
      LAYER met3 ;
        RECT 1001.050 693.640 1005.050 694.240 ;
    END
  END Y_OUT[7]
  PIN Y_OUT[8]
    DIRECTION OUTPUT ;
    USE SIGNAL ;
    ANTENNADIFFAREA 0.445500 ;
    PORT
      LAYER met3 ;
        RECT 1001.050 717.440 1005.050 718.040 ;
    END
  END Y_OUT[8]
  PIN Y_OUT[9]
    DIRECTION OUTPUT ;
    USE SIGNAL ;
    ANTENNADIFFAREA 0.445500 ;
    PORT
      LAYER met3 ;
        RECT 1001.050 724.240 1005.050 724.840 ;
    END
  END Y_OUT[9]
  PIN Y_RDY
    DIRECTION INPUT ;
    USE SIGNAL ;
    ANTENNAGATEAREA 0.126000 ;
    PORT
      LAYER met2 ;
        RECT 505.630 1011.770 505.910 1015.770 ;
    END
  END Y_RDY
  PIN Y_VLD
    DIRECTION OUTPUT ;
    USE SIGNAL ;
    ANTENNADIFFAREA 0.445500 ;
    PORT
      LAYER met3 ;
        RECT 0.000 686.840 4.000 687.440 ;
    END
  END Y_VLD
  PIN clk
    DIRECTION INPUT ;
    USE SIGNAL ;
    ANTENNAGATEAREA 1.286700 ;
    ANTENNADIFFAREA 0.434700 ;
    PORT
      LAYER met3 ;
        RECT 0.000 969.040 4.000 969.640 ;
    END
  END clk
  PIN rst_n
    DIRECTION INPUT ;
    USE SIGNAL ;
    ANTENNAGATEAREA 0.126000 ;
    PORT
      LAYER met3 ;
        RECT 0.000 952.040 4.000 952.640 ;
    END
  END rst_n
  OBS
      LAYER nwell ;
        RECT 5.330 10.795 999.310 1003.870 ;
      LAYER li1 ;
        RECT 5.520 10.795 999.120 1003.765 ;
      LAYER met1 ;
        RECT 4.210 10.640 999.510 1005.680 ;
      LAYER met2 ;
        RECT 4.230 1011.490 183.350 1011.770 ;
        RECT 184.190 1011.490 205.890 1011.770 ;
        RECT 206.730 1011.490 209.110 1011.770 ;
        RECT 209.950 1011.490 212.330 1011.770 ;
        RECT 213.170 1011.490 234.870 1011.770 ;
        RECT 235.710 1011.490 238.090 1011.770 ;
        RECT 238.930 1011.490 247.750 1011.770 ;
        RECT 248.590 1011.490 257.410 1011.770 ;
        RECT 258.250 1011.490 350.790 1011.770 ;
        RECT 351.630 1011.490 354.010 1011.770 ;
        RECT 354.850 1011.490 357.230 1011.770 ;
        RECT 358.070 1011.490 360.450 1011.770 ;
        RECT 361.290 1011.490 444.170 1011.770 ;
        RECT 445.010 1011.490 447.390 1011.770 ;
        RECT 448.230 1011.490 450.610 1011.770 ;
        RECT 451.450 1011.490 453.830 1011.770 ;
        RECT 454.670 1011.490 457.050 1011.770 ;
        RECT 457.890 1011.490 460.270 1011.770 ;
        RECT 461.110 1011.490 463.490 1011.770 ;
        RECT 464.330 1011.490 466.710 1011.770 ;
        RECT 467.550 1011.490 469.930 1011.770 ;
        RECT 470.770 1011.490 473.150 1011.770 ;
        RECT 473.990 1011.490 476.370 1011.770 ;
        RECT 477.210 1011.490 479.590 1011.770 ;
        RECT 480.430 1011.490 482.810 1011.770 ;
        RECT 483.650 1011.490 486.030 1011.770 ;
        RECT 486.870 1011.490 489.250 1011.770 ;
        RECT 490.090 1011.490 492.470 1011.770 ;
        RECT 493.310 1011.490 495.690 1011.770 ;
        RECT 496.530 1011.490 498.910 1011.770 ;
        RECT 499.750 1011.490 502.130 1011.770 ;
        RECT 502.970 1011.490 505.350 1011.770 ;
        RECT 506.190 1011.490 508.570 1011.770 ;
        RECT 509.410 1011.490 511.790 1011.770 ;
        RECT 512.630 1011.490 515.010 1011.770 ;
        RECT 515.850 1011.490 518.230 1011.770 ;
        RECT 519.070 1011.490 521.450 1011.770 ;
        RECT 522.290 1011.490 524.670 1011.770 ;
        RECT 525.510 1011.490 527.890 1011.770 ;
        RECT 528.730 1011.490 531.110 1011.770 ;
        RECT 531.950 1011.490 534.330 1011.770 ;
        RECT 535.170 1011.490 537.550 1011.770 ;
        RECT 538.390 1011.490 540.770 1011.770 ;
        RECT 541.610 1011.490 543.990 1011.770 ;
        RECT 544.830 1011.490 547.210 1011.770 ;
        RECT 548.050 1011.490 550.430 1011.770 ;
        RECT 551.270 1011.490 553.650 1011.770 ;
        RECT 554.490 1011.490 556.870 1011.770 ;
        RECT 557.710 1011.490 560.090 1011.770 ;
        RECT 560.930 1011.490 563.310 1011.770 ;
        RECT 564.150 1011.490 566.530 1011.770 ;
        RECT 567.370 1011.490 569.750 1011.770 ;
        RECT 570.590 1011.490 572.970 1011.770 ;
        RECT 573.810 1011.490 627.710 1011.770 ;
        RECT 628.550 1011.490 999.480 1011.770 ;
        RECT 4.230 4.280 999.480 1011.490 ;
        RECT 4.230 3.670 186.570 4.280 ;
        RECT 187.410 3.670 189.790 4.280 ;
        RECT 190.630 3.670 193.010 4.280 ;
        RECT 193.850 3.670 202.670 4.280 ;
        RECT 203.510 3.670 225.210 4.280 ;
        RECT 226.050 3.670 241.310 4.280 ;
        RECT 242.150 3.670 331.470 4.280 ;
        RECT 332.310 3.670 357.230 4.280 ;
        RECT 358.070 3.670 366.890 4.280 ;
        RECT 367.730 3.670 370.110 4.280 ;
        RECT 370.950 3.670 373.330 4.280 ;
        RECT 374.170 3.670 999.480 4.280 ;
      LAYER met3 ;
        RECT 3.990 970.040 1001.050 1003.845 ;
        RECT 4.400 968.640 1001.050 970.040 ;
        RECT 3.990 953.040 1001.050 968.640 ;
        RECT 4.400 951.640 1001.050 953.040 ;
        RECT 3.990 895.240 1001.050 951.640 ;
        RECT 4.400 893.840 1001.050 895.240 ;
        RECT 3.990 891.840 1001.050 893.840 ;
        RECT 4.400 890.440 1001.050 891.840 ;
        RECT 3.990 888.440 1001.050 890.440 ;
        RECT 4.400 887.040 1001.050 888.440 ;
        RECT 3.990 881.640 1001.050 887.040 ;
        RECT 4.400 880.240 1001.050 881.640 ;
        RECT 3.990 830.640 1001.050 880.240 ;
        RECT 3.990 829.240 1000.650 830.640 ;
        RECT 3.990 823.840 1001.050 829.240 ;
        RECT 3.990 822.440 1000.650 823.840 ;
        RECT 3.990 820.440 1001.050 822.440 ;
        RECT 3.990 819.040 1000.650 820.440 ;
        RECT 3.990 817.040 1001.050 819.040 ;
        RECT 3.990 815.640 1000.650 817.040 ;
        RECT 3.990 766.040 1001.050 815.640 ;
        RECT 4.400 764.640 1001.050 766.040 ;
        RECT 3.990 755.840 1001.050 764.640 ;
        RECT 4.400 754.440 1001.050 755.840 ;
        RECT 3.990 752.440 1001.050 754.440 ;
        RECT 4.400 751.040 1001.050 752.440 ;
        RECT 3.990 745.640 1001.050 751.040 ;
        RECT 4.400 744.240 1001.050 745.640 ;
        RECT 3.990 742.240 1001.050 744.240 ;
        RECT 4.400 740.840 1001.050 742.240 ;
        RECT 3.990 738.840 1001.050 740.840 ;
        RECT 4.400 737.440 1001.050 738.840 ;
        RECT 3.990 735.440 1001.050 737.440 ;
        RECT 4.400 734.040 1000.650 735.440 ;
        RECT 3.990 732.040 1001.050 734.040 ;
        RECT 3.990 730.640 1000.650 732.040 ;
        RECT 3.990 728.640 1001.050 730.640 ;
        RECT 4.400 727.240 1000.650 728.640 ;
        RECT 3.990 725.240 1001.050 727.240 ;
        RECT 4.400 723.840 1000.650 725.240 ;
        RECT 3.990 721.840 1001.050 723.840 ;
        RECT 4.400 720.440 1000.650 721.840 ;
        RECT 3.990 718.440 1001.050 720.440 ;
        RECT 4.400 717.040 1000.650 718.440 ;
        RECT 3.990 715.040 1001.050 717.040 ;
        RECT 3.990 713.640 1000.650 715.040 ;
        RECT 3.990 711.640 1001.050 713.640 ;
        RECT 3.990 710.240 1000.650 711.640 ;
        RECT 3.990 708.240 1001.050 710.240 ;
        RECT 4.400 706.840 1000.650 708.240 ;
        RECT 3.990 704.840 1001.050 706.840 ;
        RECT 4.400 703.440 1000.650 704.840 ;
        RECT 3.990 701.440 1001.050 703.440 ;
        RECT 3.990 700.040 1000.650 701.440 ;
        RECT 3.990 698.040 1001.050 700.040 ;
        RECT 4.400 696.640 1000.650 698.040 ;
        RECT 3.990 694.640 1001.050 696.640 ;
        RECT 3.990 693.240 1000.650 694.640 ;
        RECT 3.990 691.240 1001.050 693.240 ;
        RECT 4.400 689.840 1000.650 691.240 ;
        RECT 3.990 687.840 1001.050 689.840 ;
        RECT 4.400 686.440 1000.650 687.840 ;
        RECT 3.990 684.440 1001.050 686.440 ;
        RECT 4.400 683.040 1000.650 684.440 ;
        RECT 3.990 681.040 1001.050 683.040 ;
        RECT 4.400 679.640 1000.650 681.040 ;
        RECT 3.990 667.440 1001.050 679.640 ;
        RECT 4.400 666.040 1001.050 667.440 ;
        RECT 3.990 664.040 1001.050 666.040 ;
        RECT 4.400 662.640 1001.050 664.040 ;
        RECT 3.990 660.640 1001.050 662.640 ;
        RECT 4.400 659.240 1001.050 660.640 ;
        RECT 3.990 619.840 1001.050 659.240 ;
        RECT 4.400 618.440 1001.050 619.840 ;
        RECT 3.990 592.640 1001.050 618.440 ;
        RECT 4.400 591.240 1001.050 592.640 ;
        RECT 3.990 558.640 1001.050 591.240 ;
        RECT 3.990 557.240 1000.650 558.640 ;
        RECT 3.990 555.240 1001.050 557.240 ;
        RECT 3.990 553.840 1000.650 555.240 ;
        RECT 3.990 551.840 1001.050 553.840 ;
        RECT 3.990 550.440 1000.650 551.840 ;
        RECT 3.990 548.440 1001.050 550.440 ;
        RECT 3.990 547.040 1000.650 548.440 ;
        RECT 3.990 545.040 1001.050 547.040 ;
        RECT 4.400 543.640 1001.050 545.040 ;
        RECT 3.990 531.440 1001.050 543.640 ;
        RECT 4.400 530.040 1001.050 531.440 ;
        RECT 3.990 517.840 1001.050 530.040 ;
        RECT 4.400 516.440 1001.050 517.840 ;
        RECT 3.990 514.440 1001.050 516.440 ;
        RECT 4.400 513.040 1001.050 514.440 ;
        RECT 3.990 477.040 1001.050 513.040 ;
        RECT 3.990 475.640 1000.650 477.040 ;
        RECT 3.990 473.640 1001.050 475.640 ;
        RECT 3.990 472.240 1000.650 473.640 ;
        RECT 3.990 470.240 1001.050 472.240 ;
        RECT 3.990 468.840 1000.650 470.240 ;
        RECT 3.990 460.040 1001.050 468.840 ;
        RECT 3.990 458.640 1000.650 460.040 ;
        RECT 3.990 405.640 1001.050 458.640 ;
        RECT 3.990 404.240 1000.650 405.640 ;
        RECT 3.990 402.240 1001.050 404.240 ;
        RECT 3.990 400.840 1000.650 402.240 ;
        RECT 3.990 392.040 1001.050 400.840 ;
        RECT 3.990 390.640 1000.650 392.040 ;
        RECT 3.990 388.640 1001.050 390.640 ;
        RECT 3.990 387.240 1000.650 388.640 ;
        RECT 3.990 385.240 1001.050 387.240 ;
        RECT 3.990 383.840 1000.650 385.240 ;
        RECT 3.990 381.840 1001.050 383.840 ;
        RECT 3.990 380.440 1000.650 381.840 ;
        RECT 3.990 378.440 1001.050 380.440 ;
        RECT 3.990 377.040 1000.650 378.440 ;
        RECT 3.990 375.040 1001.050 377.040 ;
        RECT 3.990 373.640 1000.650 375.040 ;
        RECT 3.990 371.640 1001.050 373.640 ;
        RECT 3.990 370.240 1000.650 371.640 ;
        RECT 3.990 337.640 1001.050 370.240 ;
        RECT 3.990 336.240 1000.650 337.640 ;
        RECT 3.990 334.240 1001.050 336.240 ;
        RECT 4.400 332.840 1000.650 334.240 ;
        RECT 3.990 330.840 1001.050 332.840 ;
        RECT 4.400 329.440 1000.650 330.840 ;
        RECT 3.990 327.440 1001.050 329.440 ;
        RECT 4.400 326.040 1000.650 327.440 ;
        RECT 3.990 324.040 1001.050 326.040 ;
        RECT 4.400 322.640 1000.650 324.040 ;
        RECT 3.990 317.240 1001.050 322.640 ;
        RECT 3.990 315.840 1000.650 317.240 ;
        RECT 3.990 310.440 1001.050 315.840 ;
        RECT 3.990 309.040 1000.650 310.440 ;
        RECT 3.990 307.040 1001.050 309.040 ;
        RECT 3.990 305.640 1000.650 307.040 ;
        RECT 3.990 303.640 1001.050 305.640 ;
        RECT 4.400 302.240 1000.650 303.640 ;
        RECT 3.990 300.240 1001.050 302.240 ;
        RECT 3.990 298.840 1000.650 300.240 ;
        RECT 3.990 201.640 1001.050 298.840 ;
        RECT 4.400 200.240 1001.050 201.640 ;
        RECT 3.990 198.240 1001.050 200.240 ;
        RECT 4.400 196.840 1001.050 198.240 ;
        RECT 3.990 194.840 1001.050 196.840 ;
        RECT 4.400 193.440 1001.050 194.840 ;
        RECT 3.990 188.040 1001.050 193.440 ;
        RECT 4.400 186.640 1001.050 188.040 ;
        RECT 3.990 10.715 1001.050 186.640 ;
      LAYER met4 ;
        RECT 54.575 12.415 174.240 1001.465 ;
        RECT 176.640 12.415 177.540 1001.465 ;
        RECT 179.940 12.415 327.840 1001.465 ;
        RECT 330.240 12.415 331.140 1001.465 ;
        RECT 333.540 12.415 481.440 1001.465 ;
        RECT 483.840 12.415 484.740 1001.465 ;
        RECT 487.140 12.415 635.040 1001.465 ;
        RECT 637.440 12.415 638.340 1001.465 ;
        RECT 640.740 12.415 788.640 1001.465 ;
        RECT 791.040 12.415 791.940 1001.465 ;
        RECT 794.340 12.415 942.240 1001.465 ;
        RECT 944.640 12.415 945.540 1001.465 ;
        RECT 947.940 12.415 993.305 1001.465 ;
      LAYER met5 ;
        RECT 159.740 645.950 878.020 757.300 ;
        RECT 159.740 492.770 878.020 637.850 ;
        RECT 159.740 339.590 878.020 484.670 ;
        RECT 159.740 235.500 878.020 331.490 ;
  END
END gemm_top
END LIBRARY

